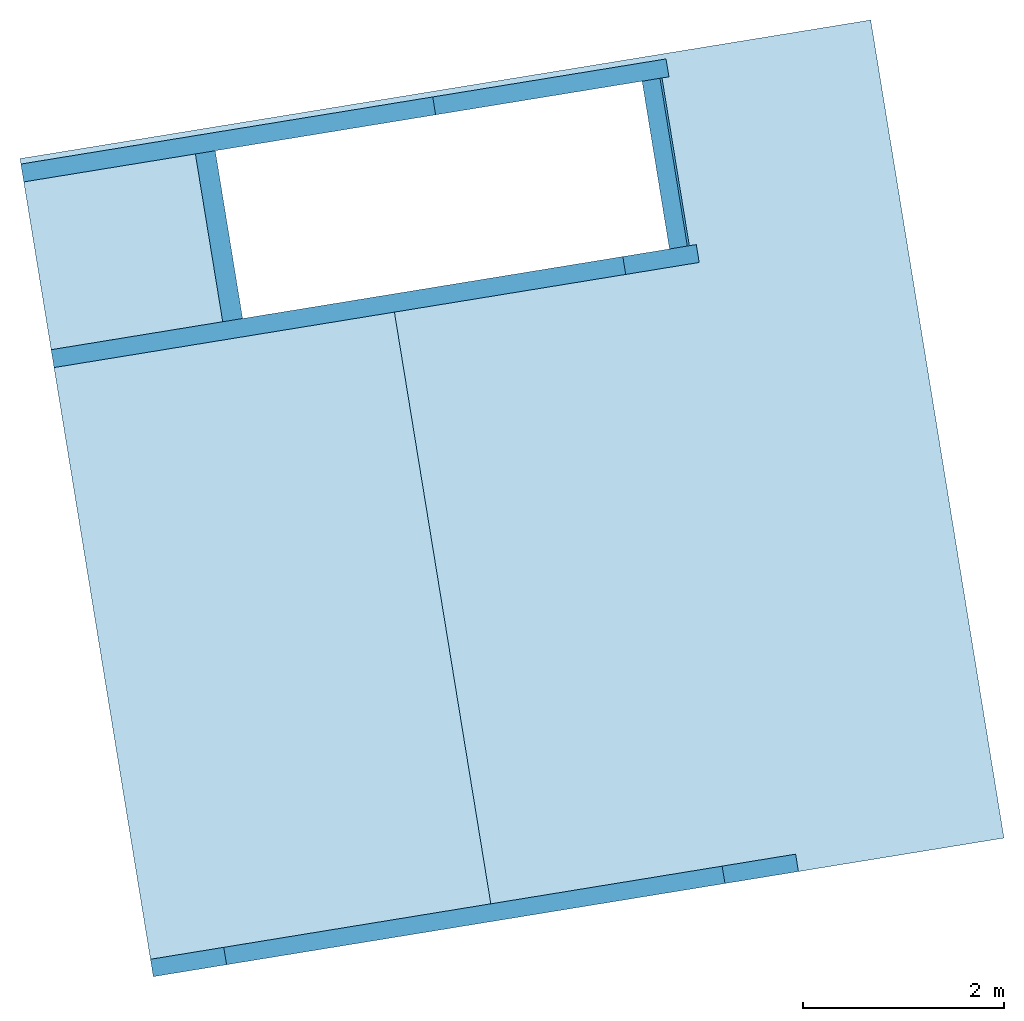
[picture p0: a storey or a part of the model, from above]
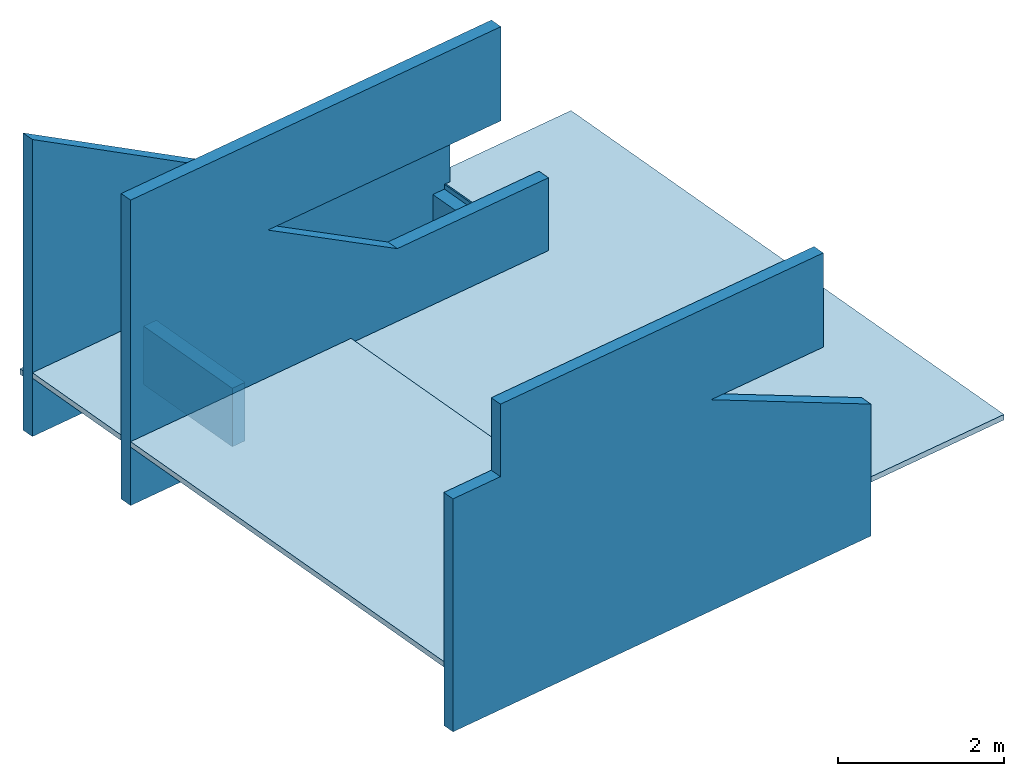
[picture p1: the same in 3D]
Properties of the parts of a building model (IFC2X3)

# File
Description: ViewDefinition [CoordinationView_V2.0]
File name: BR001-350-101.1 (EDITED).ifc (Edited by Naviate Simple BIM 2022 version 6)
Time: 2026-03-27T10:17:53+01:00
Written by: ODA SDAI 24.12
Made in: Autodesk Revit 25.4.41.14 (ENU) - IFC 25.4.0.27

# IfcProject, 01. Avinor Drift
LongName: Terminal 2 . Satellitt; Phase: Som Bygget

# IfcSite (5)
RefElevation: 0 mm
Name | RefLatitude | RefLongitude
4 x Default | 60, 17, 20, 899658 | 5, 13, 37, 654037
Default | 42, 24, 53, 508911 | -71, -15, -29, -58837

# IfcBuilding (5)
Name | LongName
br001-a-200-1-0001 | br001-a-200-1-0001

3 x Bygning (endres i Project Information) | Bygning (endres i Project Information)

# IfcBuildingStorey: Level:Level - BR001_ARK (2)
In: br001-a-200-1-0001
Name | LongName | Elevation (mm)
H01-Nivå D+0,36 | H01-Nivå D+0,36 | 51360
H02-Nivå F-3,5 m | H02-Nivå F-3,5 m | 55500

# IfcBuildingStorey: Level:Level Elektro, H01-Nivå D+0,36
In: Bygning (endres i Project Information)
LongName: H01-Nivå D+0,36; Elevation: 51360 mm

# IfcBuildingStorey: Level:NO_Nivå_Meter-VVS (2)
In: Bygning (endres i Project Information)
LongName: H01-Nivå D+0,36; Elevation: 51360 mm

# IfcBuildingStorey: Level:NSW Kote - Triangel med navn og kote, Arial 2 mm KP (2)
Name | LongName | Elevation (mm)
U01-Nivå B+3,1m | U01-Nivå B+3,1m | 47800
H01-Nivå D+0,36 | H01-Nivå D+0,36 | 51360

# IfcAnnotation, Model Lines:13462873
In: H02-Nivå F-3,5 m
ePset_Simplebim - Assembly Level: Leaf
ePset_LocationTool - Splitting: ORIGINAL

# IfcCurtainWall: Curtain Wall:A243 Innvendig glassvegg (2)
In: H01-Nivå D+0,36
ePset_Simplebim - Assembly Level: Topmost
ePset_SimplebimBasicQuantities - Width: 58 mm; Height: 3370 mm
Pset_CurtainWallCommon - Reference: Curtain Wall:A243 Innvendig glassvegg
Name (Curtain Wall:A243 Innvendig glassvegg:...) | Volume, net (Simplebim) (m3) | Length (mm)
13783014 | 0.771866 | 6245
13783059 | 0.219278 | 1755

# IfcCurtainWall: Curtain Wall:NSW Innvendig glassfelt, Curtain Wall:NSW Innvendig glassfelt:520738
In: H01-Nivå D+0,36
ePset_Simplebim - Assembly Level: Topmost
ePset_SimplebimBasicQuantities - Volume, net (Simplebim): 0.490273 m3; Width: 100 mm; Height: 3500 mm; Length: 6140 mm
Pset_CurtainWallCommon - Reference: Curtain Wall:NSW Innvendig glassfelt

# IfcDistributionPort (44)
Description: Flow
ePset_Simplebim - Assembly Level: Leaf
Name | FlowDirection | Group
Port_2817980_1 | SOURCEANDSINK
Port_2817981_1 | SOURCEANDSINK
Port_2817989_1 | SOURCEANDSINK
Port_2817990_1 | SOURCEANDSINK
Port_2817998_1 | SOURCEANDSINK
Port_2817999_1 | SOURCEANDSINK
Port_5849566_2 | SOURCEANDSINK | 360.041 Tilluft Nytt system Nord: 2
Port_5849560_0 | SOURCEANDSINK | 360.041 Tilluft Nytt system Nord: 2
Port_5849566_1 | SOURCEANDSINK | 360.041 Tilluft Nytt system Nord: 2
Port_5849560_1 | SOURCEANDSINK | 360.041 Tilluft Nytt system Nord: 2
Port_5531435_0 | SOURCEANDSINK | 3320.001.01 Brannslokking Sprinkler våt 250
Port_5531608_2 | SOURCEANDSINK | 3320.001.01 Brannslokking Sprinkler våt 250
Port_5531435_1 | SOURCEANDSINK | 3320.001.01 Brannslokking Sprinkler våt 250
Port_5531676_2 | SOURCEANDSINK | 3320.001.01 Brannslokking Sprinkler våt 250
InPort_5531471_1 | SINK | 3320.001.01 Brannslokking Sprinkler våt 250
OutPort_5531612_2 | SOURCE | 3320.001.01 Brannslokking Sprinkler våt 250
Port_5531594_0 | SOURCEANDSINK | 3320.001.01 Brannslokking Sprinkler våt 250
Port_5531608_4 | SOURCEANDSINK | 3320.001.01 Brannslokking Sprinkler våt 250
Port_5531594_1 | SOURCEANDSINK | 3320.001.01 Brannslokking Sprinkler våt 250
Port_5531612_1 | SOURCEANDSINK | 3320.001.01 Brannslokking Sprinkler våt 250
Port_5531608_3 | SOURCEANDSINK | 3320.001.01 Brannslokking Sprinkler våt 250
InPort_5531625_1 | SINK | 3320.001.01 Brannslokking Sprinkler våt 250
OutPort_5531630_2 | SOURCE | 3320.001.01 Brannslokking Sprinkler våt 250
Port_5531626_0 | SOURCEANDSINK | 3320.001.01 Brannslokking Sprinkler våt 250
Port_5531676_1 | SOURCEANDSINK | 3320.001.01 Brannslokking Sprinkler våt 250
Port_5531626_1 | SOURCEANDSINK | 3320.001.01 Brannslokking Sprinkler våt 250
Port_5531630_1 | SOURCEANDSINK | 3320.001.01 Brannslokking Sprinkler våt 250
Port_5531723_0 | SOURCEANDSINK | 3320.001.01 Brannslokking Sprinkler våt 250
Port_5531728_2 | SOURCEANDSINK | 3320.001.01 Brannslokking Sprinkler våt 250
Port_5531723_1 | SOURCEANDSINK | 3320.001.01 Brannslokking Sprinkler våt 250
Port_5531739_2 | SOURCEANDSINK | 3320.001.01 Brannslokking Sprinkler våt 250
InPort_5531725_1 | SINK | 3320.001.01 Brannslokking Sprinkler våt 250
OutPort_5531732_2 | SOURCE | 3320.001.01 Brannslokking Sprinkler våt 250
Port_5531726_0 | SOURCEANDSINK | 3320.001.01 Brannslokking Sprinkler våt 250
Port_5531728_4 | SOURCEANDSINK | 3320.001.01 Brannslokking Sprinkler våt 250
Port_5531726_1 | SOURCEANDSINK | 3320.001.01 Brannslokking Sprinkler våt 250
Port_5531732_1 | SOURCEANDSINK | 3320.001.01 Brannslokking Sprinkler våt 250
Port_5531728_3 | SOURCEANDSINK | 3320.001.01 Brannslokking Sprinkler våt 250
InPort_5531734_1 | SINK | 3320.001.01 Brannslokking Sprinkler våt 250
OutPort_5531737_2 | SOURCE | 3320.001.01 Brannslokking Sprinkler våt 250
Port_5531735_0 | SOURCEANDSINK | 3320.001.01 Brannslokking Sprinkler våt 250
Port_5531739_1 | SOURCEANDSINK | 3320.001.01 Brannslokking Sprinkler våt 250
Port_5531735_1 | SOURCEANDSINK | 3320.001.01 Brannslokking Sprinkler våt 250
Port_5531737_1 | SOURCEANDSINK | 3320.001.01 Brannslokking Sprinkler våt 250

# IfcDoor: M_Overhead-Rolling:Ny 1100 x 2200mm, M_Overhead-Rolling:Ny 1100 x 2200mm:13466188
In: H01-Nivå D+0,36
Type - ParameterTakesPrecedence: no; Sizeable: no; Material: Metal - Paint Finish - Ivory, Matte
OverallHeight: 2200 mm; OverallWidth: 4080 mm
ePset_LocationTool - Splitting: ORIGINAL
Pset_DoorCommon - Reference: M_Overhead-Rolling:Ny 1100 x 2200mm
ePset_Simplebim - Assembly Level: Leaf
ePset_SimplebimBasicQuantities - Area (Simplebim): 11.3728 m2; Area, opening (Simplebim): 8.976 m2; Height (Simplebim): 2657.2 mm; Height, opening (Simplebim): 2200 mm; Width, opening (Simplebim): 4080 mm; Width (Simplebim): 4280 mm; Length, frame (Simplebim): 9594.4 mm

# IfcFlowFitting: RS_53_PIF_UN_Elbow-EN10241_NOR:RS_53_PIF_UN_Elbow-EN10241_NOR (2)
In: H01-Nivå D+0,36
Type - Material: 3320.001
ePset_Simplebim - Assembly Level: Leaf
ePset_LocationTool - Splitting: ORIGINAL
Group: 3320.001.01 Brannslokking Sprinkler våt 250
Name (RS_53_PIF_UN_Elbow-EN10241_NOR:RS_53_PIF_UN_Elbow-EN10241_NOR:...)
5531676
5531739

# IfcFlowFitting: RS_53_PIF_UN_Reducing-Socket-EN10241_MC_gen:RS_53_PIF_UN_Reducing-Socket-EN10241_MC_gen (4)
In: H01-Nivå D+0,36
Type - Material: 3320.001
ePset_Simplebim - Assembly Level: Leaf
ePset_LocationTool - Splitting: ORIGINAL
Group: 3320.001.01 Brannslokking Sprinkler våt 250
Name (RS_53_PIF_UN_Reducing-Socket-EN10241_MC_gen:RS_53_PIF_UN_Reducing-Socket-EN10241_MC_gen:...)
5531612
5531630
5531732
5531737

# IfcFlowFitting: RS_53_PIF_UN_Tee-Reduced-EN10241_MC_gen:RS_53_PIF_UN_Tee-Reduced-EN10241_MC_gen (2)
In: H01-Nivå D+0,36
Type - Material: 3320.001
ePset_Simplebim - Assembly Level: Leaf
ePset_LocationTool - Splitting: ORIGINAL
Group: 3320.001.01 Brannslokking Sprinkler våt 250
Name (RS_53_PIF_UN_Tee-Reduced-EN10241_MC_gen:RS_53_PIF_UN_Tee-Reduced-EN10241_MC_gen:...)
5531608
5531728

# IfcFlowFitting: magicirc_elbow_full_radius_NOR:magicirc_elbow_full_radius_NOR, magicirc_elbow_full_radius_NOR:magicirc_elbow_full_radius_NOR:5849566
In: H01-Nivå D+0,36
Type - Material: 3601.001 Tilluft
ePset_Simplebim - Assembly Level: Leaf
ePset_LocationTool - Splitting: ORIGINAL
Group: 360.041 Tilluft Nytt system Nord: 2

# IfcFlowSegment: Pipe Types:Stålrør sveist og gjenget (8)
In: H01-Nivå D+0,36
Type - Material: 3320.001
ePset_Simplebim - Assembly Level: Leaf
Group: 3320.001.01 Brannslokking Sprinkler våt 250
Name (Pipe Types:Stålrør sveist og gjenget:...) | Splitting | Height (Simplebim) (mm) | Width (Simplebim) (mm) | Length (Simplebim) (mm)
5531435 | ORIGINAL | 33.7 | 33.7 | 3551.87
5531594 | ORIGINAL | 33.7 | 33.7 | 65.9543
5531626 | ORIGINAL | 33.7 | 33.7 | 65.9543
5531723 | ORIGINAL | 33.7 | 33.7 | 3551.87
5531726 | ORIGINAL | 33.7 | 33.7 | 65.9543
5531735 | ORIGINAL | 33.7 | 33.7 | 65.9543
5531609 | RESULT | 34 | 33 | 636
5531729 | RESULT | 34 | 33 | 636

# IfcFlowSegment: Round Duct:Sirkulær kanal (2)
In: H01-Nivå D+0,36
Type - Material: 3601.001 Tilluft
ePset_SimplebimBasicQuantities - Width (Simplebim): 315 mm
ePset_Simplebim - Assembly Level: Leaf
Group: 360.041 Tilluft Nytt system Nord: 2
Name (Round Duct:Sirkulær kanal:...) | Length (Simplebim) (mm) | Height (Simplebim) (mm) | Splitting
5849560 | 2585 | 315 | ORIGINAL
5849550 | 2550 | 316 | RESULT

# IfcFlowTerminal: Panel 600x600:C77-R600x600-WH-5000-HF-840-LI-4xSM (6)
In: H01-Nivå D+0,36
Type - Material: Plastic, Opaque White, <Unnamed>
Classification: UP001 (Uniformat)
ePset_Simplebim - Assembly Level: Leaf
ePset_LocationTool - Splitting: ORIGINAL
Name (Panel 600x600:C77-R600x600-WH-5000-HF-840-LI-4xSM:...)
2817980
2817981
2817989
2817990
2817998
2817999

# IfcFlowTerminal: SSP K80 HIMLING:SP-15-K80-68DGR-RS (4)
In: H01-Nivå D+0,36
Type - Material: 3320.001
ePset_Simplebim - Assembly Level: Leaf
ePset_LocationTool - Splitting: ORIGINAL
Group: 3320.001.01 Brannslokking Sprinkler våt 250
Name (SSP K80 HIMLING:SP-15-K80-68DGR-RS:...)
5531471
5531625
5531725
5531734

# IfcMember: Rectangular Mullion:6.66x12 (10)
In: H01-Nivå D+0,36
Type - PredefinedType: MULLION; Material: T2 - Rubber
ePset_Simplebim - Assembly Level: Leaf
ePset_LocationTool - Splitting: ORIGINAL
Pset_MemberCommon - Reference: Rectangular Mullion:6.66x12
ePset_SimplebimBasicQuantities - Width (Simplebim): 6.6 mm; Length (Simplebim): 12 mm
Name (Rectangular Mullion:6.66x12:...) | Height (Simplebim) (mm) | Area, sides, net (Simplebim) (m2) | Volume, net (Simplebim) (m3) | Weight, as steel (Simplebim) (kg)
13783367 | 2196.67 | 0.0818744 | 0.000173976 | 1.36571
13783399 | 2196.67 | 0.0818744 | 0.000173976 | 1.36571
13783431 | 2196.67 | 0.0818744 | 0.000173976 | 1.36571
13783473 | 2196.67 | 0.0818744 | 0.000173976 | 1.36571
13786006 | 1073.33 | 0.0400864 | 0.000085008 | 0.667313
13786007 | 1073.33 | 0.0400864 | 0.000085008 | 0.667313
13786008 | 1073.33 | 0.0400864 | 0.000085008 | 0.667313
13786009 | 1073.33 | 0.0400864 | 0.000085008 | 0.667313
13783512 | 2196.67 | 0.0818744 | 0.000173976 | 1.36571
13785952 | 1073.33 | 0.0400864 | 0.000085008 | 0.667313

# IfcMember: Rectangular Mullion:NSW 50x50 Add on (29)
In: H01-Nivå D+0,36
Type - PredefinedType: MULLION; Material: Metal - Aluminium
Pset_MemberCommon - Reference: Rectangular Mullion:NSW 50x50 Add on
ePset_Simplebim - Assembly Level: Leaf
ePset_LocationTool - Splitting: ORIGINAL
ePset_SimplebimBasicQuantities - Width (Simplebim): 50 mm
Name (Rectangular Mullion:NSW 50x50 Add on:...) | Volume, net (Simplebim) (m3) | Area, sides, net (Simplebim) (m2) | Height (Simplebim) (mm) | Length (Simplebim) (mm) | Weight, as steel (Simplebim) (kg)
13783553 | 0.00268333 | 0.219667 | 1073.33 | 50 | 21.0642
13783554 | 0.00549167 | 0.444333 | 2196.67 | 50 | 43.1096
13783555 | 0.00302917 | 0.247333 | 50 | 1211.67 | 23.779
13783556 | 0.0032125 | 0.263036 | 50 | 1310 | 25.2181
13783557 | 0.0032125 | 0.263036 | 50 | 1310 | 25.2181
13783558 | 0.00325 | 0.265 | 50 | 1300 | 25.5125
13783559 | 0.00302917 | 0.247333 | 50 | 1211.67 | 23.779
13783560 | 0.00302917 | 0.247333 | 50 | 1211.67 | 23.779
13783561 | 0.00325 | 0.265 | 50 | 1300 | 25.5125
13783562 | 0.00302917 | 0.247333 | 50 | 1211.67 | 23.779
13783563 | 0.00302917 | 0.247333 | 50 | 1211.67 | 23.779
13783564 | 0.00302917 | 0.247333 | 50 | 1211.67 | 23.779
13786015 | 0.00549167 | 0.444333 | 2196.67 | 50 | 43.1096
13786016 | 0.00268333 | 0.219667 | 1073.33 | 50 | 21.0642
13786048 | 0.00301267 | 0.246013 | 50 | 1205.07 | 23.6494
13786049 | 0.00301267 | 0.246013 | 50 | 1205.07 | 23.6494
13786050 | 0.0032335 | 0.26368 | 50 | 1293.4 | 25.383
13786051 | 0.00311675 | 0.25434 | 50 | 1246.7 | 24.4665
13786052 | 0.00289592 | 0.236673 | 50 | 1158.37 | 22.7329
13783580 | 0.00268333 | 0.219667 | 1073.33 | 50 | 21.0642
13783581 | 0.00549167 | 0.444333 | 2196.67 | 50 | 43.1096
13783582 | 0.00214375 | 0.177536 | 50 | 882.5 | 16.8284
13783583 | 0.00218125 | 0.1795 | 50 | 872.5 | 17.1228
13783584 | 0.00218125 | 0.1795 | 50 | 872.5 | 17.1228
13783585 | 0.00214375 | 0.177536 | 50 | 882.5 | 16.8284
13785958 | 0.00549167 | 0.444333 | 2196.67 | 50 | 43.1096
13785959 | 0.00268333 | 0.219667 | 1073.33 | 50 | 21.0642
13786037 | 0.002048 | 0.16884 | 50 | 819.2 | 16.0768
13786038 | 0.002048 | 0.16884 | 50 | 819.2 | 16.0768

# IfcMember: Rectangular Mullion:NSW Innvendig spross 50x100 mm (32)
In: H01-Nivå D+0,36
Type - PredefinedType: MULLION; Material: Laminate - Ivory, Matte
ePset_Simplebim - Assembly Level: Leaf
Pset_MemberCommon - Reference: Rectangular Mullion:NSW Innvendig spross 50x100 mm
ePset_LocationTool - Splitting: ORIGINAL
Name (Rectangular Mullion:NSW Innvendig spross 50x100 mm:...) | Volume, net (Simplebim) (m3) | Height (Simplebim) (mm) | Width (Simplebim) (mm) | Length (Simplebim) (mm) | Area, sides, net (Simplebim) (m2) | Weight, as steel (Simplebim) (kg)
520742 | 0.004625 | 50 | 100 | 925 | 0.2875 | 36.3063
520744 | 0.01125 | 2250 | 50 | 100 | 0.685 | 88.3125
520745 | 0.00575 | 1150 | 50 | 100 | 0.355 | 45.1375
521027 | 0.004875 | 50 | 100 | 975 | 0.3025 | 38.2688
521029 | 0.01125 | 2250 | 50 | 100 | 0.685 | 88.3125
521124 | 0.00389 | 50 | 100 | 778 | 0.2434 | 30.5365
521126 | 0.01125 | 2250 | 50 | 100 | 0.685 | 88.3125
521431 | 0.006 | 1200 | 50 | 100 | 0.37 | 47.1
521432 | 0.0115 | 2300 | 50 | 100 | 0.7 | 90.275
521433 | 0.004625 | 50 | 100 | 925 | 0.2875 | 36.3063
521434 | 0.00389 | 50 | 100 | 778 | 0.2434 | 30.5365
521435 | 0.004625 | 50 | 100 | 925 | 0.2875 | 36.3063
521436 | 0.006 | 1200 | 50 | 100 | 0.37 | 47.1
521437 | 0.006 | 1200 | 50 | 100 | 0.37 | 47.1
521632 | 0.00389 | 50 | 100 | 778 | 0.2434 | 30.5365
521634 | 0.00389 | 50 | 100 | 778 | 0.2434 | 30.5365
521636 | 0.006125 | 1225 | 50 | 100 | 0.3775 | 48.0813
521838 | 0.00389 | 50 | 100 | 778 | 0.2434 | 30.5365
521840 | 0.00389 | 50 | 100 | 778 | 0.2434 | 30.5365
521842 | 0.006125 | 1225 | 50 | 100 | 0.3775 | 48.0813
521907 | 0.00389 | 50 | 100 | 778 | 0.2434 | 30.5365
521909 | 0.00389 | 50 | 100 | 778 | 0.2434 | 30.5365
521911 | 0.006125 | 1225 | 50 | 100 | 0.3775 | 48.0813
521987 | 0.00389 | 50 | 100 | 778 | 0.2434 | 30.5365
521989 | 0.00389 | 50 | 100 | 778 | 0.2434 | 30.5365
521991 | 0.006125 | 1225 | 50 | 100 | 0.3775 | 48.0813
13466135 | 0.00975 | 1950 | 50 | 100 | 0.595 | 76.5375
13466136 | 0.00975 | 1950 | 50 | 100 | 0.595 | 76.5375
13466234 | 0.00475 | 50 | 100 | 950 | 0.295 | 37.2875
13466236 | 0.000125 | 50 | 25 | 100 | 0.0175 | 0.98125
13466237 | 0.000125 | 50 | 25 | 100 | 0.0175 | 0.98125
13466241 | 0.005 | 50 | 100 | 1000 | 0.31 | 39.25

# IfcPlate: System Panel:NSW Utvendig glass (16)
In: H01-Nivå D+0,36
Type - PredefinedType: CURTAIN_PANEL; Material: _NSW Glass
ePset_Simplebim - Assembly Level: Leaf
Pset_PlateCommon - Reference: System Panel:NSW Utvendig glass
ePset_LocationTool - Splitting: ORIGINAL
Name (System Panel:NSW Utvendig glass:...) | Volume, net (Simplebim) (m3) | Weight, as steel (Simplebim) (kg) | Area, largest surface, net (Simplebim) (m2)
520739 | 0.0740925 | 581.626 | 2.05812
521117 | 0.0740925 | 581.626 | 2.05812
13783015 | 0.0905611 | 710.905 | 2.51559
13783470 | 0.0942121 | 739.565 | 2.617
13783428 | 0.0942121 | 739.565 | 2.617
13783397 | 0.101118 | 793.776 | 2.80883
13783364 | 0.097467 | 765.116 | 2.70742
13785986 | 0.0437168 | 343.177 | 1.21435
13785987 | 0.0454792 | 357.012 | 1.26331
13785988 | 0.0454792 | 357.012 | 1.26331
13785989 | 0.0488129 | 383.181 | 1.35591
13785990 | 0.0470505 | 369.346 | 1.30696
13783060 | 0.0640451 | 502.754 | 1.77903
13783510 | 0.0640451 | 502.754 | 1.77903
13785940 | 0.0309166 | 242.695 | 0.858795
13785941 | 0.0309166 | 242.695 | 0.858795

# IfcPlate: System Panel:Solid panel (7)
In: H01-Nivå D+0,36
Type - PredefinedType: CURTAIN_PANEL; Material: Metal - Aluminium(KP)
Pset_PlateCommon - Reference: System Panel:Solid panel
ePset_Simplebim - Assembly Level: Leaf
ePset_LocationTool - Splitting: ORIGINAL
Name (System Panel:Solid panel:...) | Volume, net (Simplebim) (m3) | Weight, as steel (Simplebim) (kg) | Area, largest surface, net (Simplebim) (m2)
521415 | 0.0260156 | 204.223 | 1.04062
521416 | 0.0218812 | 171.768 | 0.87525
521625 | 0.0218812 | 171.768 | 0.87525
521829 | 0.0218812 | 171.768 | 0.87525
521898 | 0.0218812 | 171.768 | 0.87525
521978 | 0.0218812 | 171.768 | 0.87525
521417 | 0.0260156 | 204.223 | 1.04062

# IfcSlab: 180*6550, PLASSTØPTVEGG
In: U01-Nivå B+3,1m
Type - PredefinedType: FLOOR
Description: 180*6550
ePset_SimplebimBasicQuantities - Area, largest surface, net (Simplebim): 17.6434 m2; Volume, net (Simplebim): 3.17584 m3; Perimeter (Simplebim): 8301.56 mm; Thickness (Simplebim): 4387.38 mm; Area, sides, net (Simplebim): 36.4221 m2; Area, top, net (Simplebim): 1.28821 m2
ePset_LocationTool - Splitting: RESULT
ePset_Simplebim - Assembly Level: Leaf
Pset_SlabCommon - Reference: 180*6550

# IfcSlab: 180*8650 (2)
In: U01-Nivå B+3,1m
Type - PredefinedType: FLOOR
Description: 180*8650
ePset_Simplebim - Assembly Level: Leaf
Pset_SlabCommon - Reference: 180*8650
ePset_SimplebimBasicQuantities - Thickness (Simplebim): 4490 mm
ePset_LocationTool - Splitting: RESULT
Name | Area, sides, net (Simplebim) (m2) | Area, top, net (Simplebim) (m2) | Area, largest surface, net (Simplebim) (m2) | Volume, net (Simplebim) (m3) | Perimeter (Simplebim) (mm)
PLASSTØPTVEGG | 53.2058 | 1.489 | 25.9188 | 4.53827 | 11849.9
PLASSTØPTVEGG | 49.8889 | 1.87852 | 24.2412 | 4.36342 | 11111.1

# IfcSlab: 80*12000, GULVPÅGRUNN
In: U01-Nivå B+3,1m
Type - PredefinedType: FLOOR
Description: 80*12000
ePset_LocationTool - Splitting: RESULT
ePset_Simplebim - Assembly Level: Leaf
ePset_SimplebimBasicQuantities - Area, largest surface, net (Simplebim): 36.6841 m2; Area, top, net (Simplebim): 36.6841 m2; Volume, net (Simplebim): 2.93486 m3; Area, sides, net (Simplebim): 3.18411 m2; Perimeter (Simplebim): 39797.5 mm; Thickness (Simplebim): 80.0076 mm
Pset_SlabCommon - Reference: 80*12000

# IfcSlab: 80*1690, GULVPÅGRUNN
In: U01-Nivå B+3,1m
Type - PredefinedType: FLOOR
Description: 80*1690
Pset_SlabCommon - Reference: 80*1690
ePset_SimplebimBasicQuantities - Thickness (Simplebim): 80.0006 mm; Area, largest surface, net (Simplebim): 3.25887 m2; Perimeter (Simplebim): 7236.64 mm; Area, sides, net (Simplebim): 0.578935 m2; Volume, net (Simplebim): 0.260709 m3; Area, top, net (Simplebim): 3.25887 m2
ePset_Simplebim - Assembly Level: Leaf
ePset_LocationTool - Splitting: RESULT

# IfcSlab: 80*4500, GULVPÅGRUNN
In: U01-Nivå B+3,1m
Type - PredefinedType: FLOOR
Description: 80*4500
ePset_Simplebim - Assembly Level: Leaf
Pset_SlabCommon - Reference: 80*4500
ePset_LocationTool - Splitting: RESULT
ePset_SimplebimBasicQuantities - Volume, net (Simplebim): 1.63463 m3; Area, largest surface, net (Simplebim): 20.4329 m2; Area, top, net (Simplebim): 20.4329 m2; Thickness (Simplebim): 80 mm; Area, sides, net (Simplebim): 1.50212 m2; Perimeter (Simplebim): 18776.5 mm

# IfcSlab: Floor:B250 - Betong - 500 mm, Floor:B250 - Betong - 500 mm:6508551
In: H01-Nivå D+0,36
Type - PredefinedType: FLOOR; Material: _NSW Betong 500 mm
ePset_Simplebim - Assembly Level: Leaf
ePset_SimplebimBasicQuantities - Area, top, net (Simplebim): 70.6086 m2; Volume, net (Simplebim): 35.3043 m3; Area, largest surface, net (Simplebim): 70.6086 m2; Area, sides, net (Simplebim): 16.809 m2; Thickness (Simplebim): 500 mm; Perimeter (Simplebim): 33617.9 mm
ePset_LocationTool - Splitting: RESULT
Pset_SlabCommon - Reference: Floor:B250 - Betong - 500 mm

# IfcSlab: Floor:Eksisterende flis 300 x 300, Floor:Eksisterende flis 300 x 300:13846988
In: H01-Nivå D+0,36
Type - PredefinedType: FLOOR; Material: A255 - Flis 300 x 300 10 mm
ePset_Simplebim - Assembly Level: Leaf
Pset_SlabCommon - Reference: Floor:Eksisterende flis 300 x 300
ePset_LocationTool - Splitting: RESULT
ePset_SimplebimBasicQuantities - Area, top, net (Simplebim): 39.9042 m2; Area, largest surface, net (Simplebim): 39.9039 m2; Volume, net (Simplebim): 0.399039 m3; Area, sides, net (Simplebim): 0.252116 m2; Perimeter (Simplebim): 25211.6 mm; Thickness (Simplebim): 10 mm

# IfcSlab: Floor:Eksisterende terrazzoflis, Floor:Eksisterende terrazzoflis:13875910
In: H01-Nivå D+0,36
Type - PredefinedType: FLOOR; Material: A255 - Flis 10 mm
ePset_LocationTool - Splitting: RESULT
ePset_Simplebim - Assembly Level: Leaf
Pset_SlabCommon - Reference: Floor:Eksisterende terrazzoflis
ePset_SimplebimBasicQuantities - Volume, net (Simplebim): 0.174467 m3; Area, largest surface, net (Simplebim): 17.4467 m2; Area, sides, net (Simplebim): 0.335605 m2; Area, top, net (Simplebim): 17.447 m2; Thickness (Simplebim): 10 mm; Perimeter (Simplebim): 33560.5 mm

# IfcSlab: Floor:Generic 150mm (2)
In: H01-Nivå D+0,36
Type - PredefinedType: FLOOR; Material: <Unnamed> 150 mm
ePset_Simplebim - Assembly Level: Leaf
Pset_SlabCommon - Reference: Floor:Generic 150mm
ePset_SimplebimBasicQuantities - Thickness (Simplebim): 150 mm
ePset_LocationTool - Splitting: RESULT
Name (Floor:Generic 150mm:...) | Area, top, net (Simplebim) (m2) | Area, largest surface, net (Simplebim) (m2) | Perimeter (Simplebim) (mm) | Area, sides, net (Simplebim) (m2) | Volume, net (Simplebim) (m3)
13783188 | 11.7179 | 11.7177 | 16601.4 | 2.4902 | 1.75765
518160 | 34.1995 | 34.1993 | 23415.3 | 3.51229 | 5.12989

# IfcSlab: Floor:Nytt gulv, Floor:Nytt gulv:13849383
In: H01-Nivå D+0,36
Type - PredefinedType: FLOOR; Material: _NSW Betong 10 mm
ePset_SimplebimBasicQuantities - Area, largest surface, net (Simplebim): 11.2064 m2; Area, sides, net (Simplebim): 0.163658 m2; Perimeter (Simplebim): 16365.8 mm; Volume, net (Simplebim): 0.112064 m3; Thickness (Simplebim): 10 mm; Area, top, net (Simplebim): 11.2065 m2
ePset_Simplebim - Assembly Level: Leaf
ePset_LocationTool - Splitting: RESULT
Pset_SlabCommon - Reference: Floor:Nytt gulv

# IfcWall: 1270*200, PLASSTØPTVEGG
In: U01-Nivå B+3,1m
Type - Material: CONCRETE/B35
Description: 1270*200
Pset_WallCommon - Reference: 1270*200
ePset_Simplebim - Assembly Level: Leaf
ePset_SimplebimBasicQuantities - Area, side, gross, larger (Simplebim): 1.4534 m2; Area, side, net, larger (Simplebim): 1.4534 m2; Area, side, net, average (Simplebim): 1.4534 m2; Area, side, gross, average (Simplebim): 1.4534 m2; Area, largest surface, net (Simplebim): 1.4534 m2; Area, side, gross, smaller (Simplebim): 1.4534 m2; Area, side, net, smaller (Simplebim): 1.4534 m2; Volume, net (Simplebim): 0.29068 m3; Thickness (Simplebim): 200 mm; Height (Simplebim): 860 mm; Length (Simplebim): 1690 mm; Area, side, gross, AABB (Simplebim): 1.4534 m2
ePset_LocationTool - Splitting: RESULT

# IfcWall: 1280*200, PLASSTØPTVEGG
In: U01-Nivå B+3,1m
Type - Material: CONCRETE/B35
Description: 1280*200
Pset_WallCommon - Reference: 1280*200
ePset_SimplebimBasicQuantities - Area, side, net, larger (Simplebim): 1.4703 m2; Area, side, gross, larger (Simplebim): 1.4703 m2; Area, largest surface, net (Simplebim): 1.4703 m2; Area, side, gross, average (Simplebim): 1.4703 m2; Area, side, net, average (Simplebim): 1.4703 m2; Area, side, net, smaller (Simplebim): 1.4703 m2; Area, side, gross, smaller (Simplebim): 1.4703 m2; Thickness (Simplebim): 200 mm; Height (Simplebim): 870 mm; Length (Simplebim): 1690 mm; Volume, net (Simplebim): 0.272766 m3; Area, side, gross, AABB (Simplebim): 1.4703 m2
ePset_Simplebim - Assembly Level: Leaf
ePset_LocationTool - Splitting: RESULT

# IfcWall: 1385*180, PLASSTØPTVEGG
In: H01-Nivå D+0,36
Type - Material: CONCRETE/C35/45 55428
Description: 1385*180
ePset_Simplebim - Assembly Level: Leaf
Pset_WallCommon - Reference: 1385*180
ePset_SimplebimBasicQuantities - Thickness (Simplebim): 180.026 mm; Area, side, gross, smaller (Simplebim): 8.2546 m2; Area, side, net, smaller (Simplebim): 8.2546 m2; Area, side, net, average (Simplebim): 8.2546 m2; Area, side, gross, average (Simplebim): 8.2546 m2; Area, largest surface, net (Simplebim): 8.2546 m2; Area, side, gross, larger (Simplebim): 8.2546 m2; Area, side, net, larger (Simplebim): 8.2546 m2; Area, side, gross, AABB (Simplebim): 8.2546 m2; Height (Simplebim): 1385 mm; Length (Simplebim): 5960 mm; Volume, net (Simplebim): 1.48583 m3
ePset_LocationTool - Splitting: ORIGINAL

# IfcWall: Basic Wall:A242 - Standard 170 (5)
Type - PredefinedType: STANDARD; Material: _NSW Standard 170 mm
ePset_Simplebim - Assembly Level: Leaf
ePset_SimplebimBasicQuantities - Thickness (Simplebim): 170 mm
Pset_WallCommon - Reference: Basic Wall:A242 - Standard 170
Name (Basic Wall:A242 - Standard 170:...) | In | Splitting | Area, side, net, average (Simplebim) (m2) = Area, side, net, larger (Simplebim) (m2) = Area, side, net, smaller (Simplebim) (m2) = Area, largest surface, net (Simplebim) (m2) | Area, side, gross, average (Simplebim) (m2) = Area, side, gross, larger (Simplebim) (m2) = Area, side, gross, smaller (Simplebim) (m2) | Area, side, gross, AABB (Simplebim) (m2) | Height (Simplebim) (mm) | Length (Simplebim) (mm) | Volume, net (Simplebim) (m3)
11617404 | H01-Nivå D+0,36 | ORIGINAL | 2.47166 | 2.47166 | 2.47758 | 1020 | 2429 | 0.420182
864832 | H01-Nivå D+0,36 | RESULT | 18.0117 | 18.0117 | 19.9549 | 3520 | 5669 | 2.99504
517194 | H01-Nivå D+0,36 | RESULT | 19.7921 | 26.3301 | 22.8941 | 3520 | 6504 | 3.2977
13455392 | H02-Nivå F-3,5 m | RESULT | 0.54162 | 0.54162 | 0.54162 | 1020 | 531 | 0.0920754
13308862 | H01-Nivå D+0,36 | RESULT | 1.4168 | 1.4168 | 1.4168 | 2300 | 616 | 0.240856

# IfcWall: Basic Wall:NSW Innvendig - Glassvegg 50, Basic Wall:NSW Innvendig - Glassvegg 50:13458286
In: H01-Nivå D+0,36
Type - PredefinedType: STANDARD; Material: Glass 50 mm
Pset_WallCommon - Reference: Basic Wall:NSW Innvendig - Glassvegg 50
ePset_LocationTool - Splitting: RESULT
ePset_Simplebim - Assembly Level: Leaf
ePset_SimplebimBasicQuantities - Volume, net (Simplebim): 0.025296 m3; Area, side, gross, AABB (Simplebim): 0.50592 m2; Area, side, net, larger (Simplebim): 0.50592 m2; Area, side, gross, larger (Simplebim): 0.50592 m2; Area, side, gross, average (Simplebim): 0.50592 m2; Area, side, net, average (Simplebim): 0.50592 m2; Area, largest surface, net (Simplebim): 0.50592 m2; Area, side, net, smaller (Simplebim): 0.50592 m2; Area, side, gross, smaller (Simplebim): 0.50592 m2; Thickness (Simplebim): 50 mm; Height (Simplebim): 620 mm; Length (Simplebim): 816 mm

# IfcWallStandardCase: Basic Wall:A242 - Standard 170 (4)
In: H01-Nivå D+0,36
Type - PredefinedType: STANDARD; Material: _NSW Standard 170 mm
ePset_Simplebim - Assembly Level: Leaf
ePset_LocationTool - Splitting: ORIGINAL
ePset_SimplebimBasicQuantities - Thickness (Simplebim): 170 mm
Pset_WallCommon - Reference: Basic Wall:A242 - Standard 170
Name (Basic Wall:A242 - Standard 170:...) | Area, side, gross, AABB (Simplebim) (m2) | Length (Simplebim) (mm) | Area, side, gross, average (Simplebim) (m2) = Area, side, gross, larger (Simplebim) (m2) = Area, side, gross, smaller (Simplebim) (m2) | Volume, net (Simplebim) (m3) | Height (Simplebim) (mm) | Area, largest surface, net (Simplebim) (m2) | Area, side, net, smaller (Simplebim) (m2) = Area, side, net, average (Simplebim) (m2) = Area, side, net, larger (Simplebim) (m2)
13465912 | 8.18 | 4090 | 8.996 | 0.0034 | 2000 | 0.34 | 0.02
13616055 | 4.95491 | 1700 | 4.95491 | 0.842335 | 2914.66 | 4.95491 | 4.95491
13783174 | 0.83 | 830 | 2.741 | 0.1411 | 1000 | 0.83 | 0.83
14039332 | 2.39088 | 2344 | 2.39088 | 0.40645 | 1020 | 2.39088 | 2.39088
